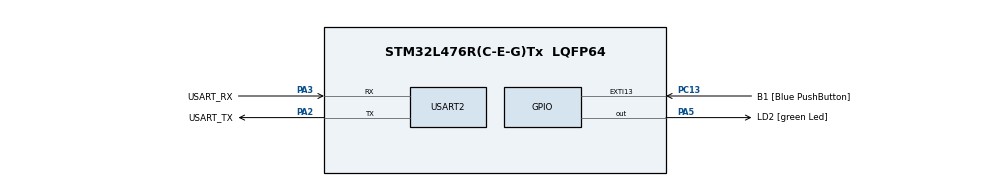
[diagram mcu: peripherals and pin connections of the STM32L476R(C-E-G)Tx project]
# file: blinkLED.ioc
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Mcu.Family=STM32L4
Mcu.Name=STM32L476R(C-E-G)Tx
Mcu.Package=LQFP64
NVIC.PriorityGroup=NVIC_PRIORITYGROUP_4
NVIC.TIM6_DAC_IRQn=true\:0\:0\:false\:false\:true\:true
PA13\ (JTMS-SWDIO).GPIO_Label=TMS
PA13\ (JTMS-SWDIO).Mode=Serial_Wire
PA13\ (JTMS-SWDIO).Signal=SYS_JTMS-SWDIO
PA14\ (JTCK-SWCLK).GPIO_Label=TCK
PA14\ (JTCK-SWCLK).Mode=Serial_Wire
PA14\ (JTCK-SWCLK).Signal=SYS_JTCK-SWCLK
PA2.GPIO_Label=USART_TX
PA2.GPIO_Mode=GPIO_MODE_AF_PP
PA2.GPIO_PuPd=GPIO_NOPULL
PA2.GPIO_Speed=GPIO_SPEED_FREQ_VERY_HIGH
PA2.Mode=Asynchronous
PA2.Signal=USART2_TX
PA3.GPIO_Label=USART_RX
PA3.GPIO_Mode=GPIO_MODE_AF_PP
PA3.GPIO_PuPd=GPIO_NOPULL
PA3.GPIO_Speed=GPIO_SPEED_FREQ_VERY_HIGH
PA3.Mode=Asynchronous
PA3.Signal=USART2_RX
PA5.GPIO_Label=LD2 [green Led]
PA5.GPIO_ModeDefaultOutputPP=GPIO_MODE_OUTPUT_PP
PA5.GPIO_PuPd=GPIO_NOPULL
PA5.GPIO_Speed=GPIO_SPEED_FREQ_LOW
PA5.Signal=GPIO_Output
PB3\ (JTDO-TRACESWO).GPIO_Label=SWO
PB3\ (JTDO-TRACESWO).Signal=SYS_JTDO-SWO
PC13.GPIO_Label=B1 [Blue PushButton]
PC13.GPIO_ModeDefaultEXTI=GPIO_MODE_IT_FALLING
PC13.GPIO_PuPd=GPIO_NOPULL
PC13.Signal=GPXTI13
PC14-OSC32_IN\ (PC14).Mode=LSE-External-Oscillator
PC14-OSC32_IN\ (PC14).Signal=RCC_OSC32_IN
PC15-OSC32_OUT\ (PC15).Mode=LSE-External-Oscillator
PC15-OSC32_OUT\ (PC15).Signal=RCC_OSC32_OUT
PH0-OSC_IN\ (PH0).Signal=RCC_OSC_IN
PH1-OSC_OUT\ (PH1).Signal=RCC_OSC_OUT
ProjectManager.HeapSize=0x200
ProjectManager.StackSize=0x400
ProjectManager.TargetToolchain=SW4STM32
RCC.ADCFreq_Value=64000000
RCC.AHBFreq_Value=16000000
RCC.APB1Freq_Value=16000000
RCC.APB1TimFreq_Value=16000000
RCC.APB2Freq_Value=16000000
RCC.APB2TimFreq_Value=16000000
RCC.CortexFreq_Value=16000000
RCC.HCLKFreq_Value=16000000
RCC.HSE_VALUE=8000000
RCC.HSI_VALUE=16000000
RCC.MSI_VALUE=4000000
RCC.PLLN=10
RCC.PLLSourceVirtual=RCC_PLLSOURCE_HSI
RCC.PREFETCH_ENABLE=1
RCC.SYSCLKFreq_VALUE=16000000
RCC.SYSCLKSource=RCC_SYSCLKSOURCE_HSI
RCC.USBFreq_Value=64000000
RCC.VCOOutputFreq_Value=160000000
TIM6.Period=1000
TIM6.Prescaler=16000
USART2.VirtualMode-Asynchronous=VM_ASYNC
VP_TIM6_VS_ClockSourceINT.Mode=Enable_Timer
board=NUCLEO-L476RG

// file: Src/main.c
/**
  ******************************************************************************
  * @file           : main.c
  * @brief          : Main program body
  ******************************************************************************
  ** This notice applies to any and all portions of this file
  * that are not between comment pairs USER CODE BEGIN and
  * USER CODE END. Other portions of this file, whether
  * inserted by the user or by software development tools
  * are owned by their respective copyright owners.
  *
  * COPYRIGHT(c) 2018 STMicroelectronics
  *
  * Redistribution and use in source and binary forms, with or without modification,
  * are permitted provided that the following conditions are met:
  *   1. Redistributions of source code must retain the above copyright notice,
  *      this list of conditions and the following disclaimer.
  *   2. Redistributions in binary form must reproduce the above copyright notice,
  *      this list of conditions and the following disclaimer in the documentation
  *      and/or other materials provided with the distribution.
  *   3. Neither the name of STMicroelectronics nor the names of its contributors
  *      may be used to endorse or promote products derived from this software
  *      without specific prior written permission.
  *
  * THIS SOFTWARE IS PROVIDED BY THE COPYRIGHT HOLDERS AND CONTRIBUTORS "AS IS"
  * AND ANY EXPRESS OR IMPLIED WARRANTIES, INCLUDING, BUT NOT LIMITED TO, THE
  * IMPLIED WARRANTIES OF MERCHANTABILITY AND FITNESS FOR A PARTICULAR PURPOSE ARE
  * DISCLAIMED. IN NO EVENT SHALL THE COPYRIGHT HOLDER OR CONTRIBUTORS BE LIABLE
  * FOR ANY DIRECT, INDIRECT, INCIDENTAL, SPECIAL, EXEMPLARY, OR CONSEQUENTIAL
  * DAMAGES (INCLUDING, BUT NOT LIMITED TO, PROCUREMENT OF SUBSTITUTE GOODS OR
  * SERVICES; LOSS OF USE, DATA, OR PROFITS; OR BUSINESS INTERRUPTION) HOWEVER
  * CAUSED AND ON ANY THEORY OF LIABILITY, WHETHER IN CONTRACT, STRICT LIABILITY,
  * OR TORT (INCLUDING NEGLIGENCE OR OTHERWISE) ARISING IN ANY WAY OUT OF THE USE
  * OF THIS SOFTWARE, EVEN IF ADVISED OF THE POSSIBILITY OF SUCH DAMAGE.
  *
  ******************************************************************************
  */
#include "main.h"
#include "stm32l4xx_hal.h"

TIM_HandleTypeDef htim6;

UART_HandleTypeDef huart2;

/* USER CODE BEGIN PV */
/* Private variables ---------------------------------------------------------*/

/* USER CODE END PV */

void SystemClock_Config(void);
static void MX_GPIO_Init(void);
static void MX_USART2_UART_Init(void);
static void MX_TIM6_Init(void);

/* USER CODE BEGIN PFP */
/* Private function prototypes -----------------------------------------------*/

/* USER CODE END PFP */

/* USER CODE BEGIN 0 */
void HAL_TIM_PeriodElapsedCallback(TIM_HandleTypeDef *htim)		//function that takes a structure as a parameter
{																//the ISR is handled by HAL
	if(htim->Instance == TIM6)									//if the instance is equal to timer 6 value
		HAL_GPIO_TogglePin(GPIOA, GPIO_PIN_5);					//this function handles the LED blinking, the GPIOA is the port and the GPIO_PIN_5 is the pin number on the port
}
/* USER CODE END 0 */

int main(void)
{

  /* MCU Configuration----------------------------------------------------------*/

  /* Reset of all peripherals, Initializes the Flash interface and the Systick. */
  HAL_Init();

  /* Configure the system clock */
  SystemClock_Config();

  /* Initialize all configured peripherals */
  MX_GPIO_Init();
  MX_USART2_UART_Init();
  MX_TIM6_Init();
  /* USER CODE BEGIN 2 */
  //HAL_TIM_Base_Start_IT(&htim6);					//this function will start the timer6 peripheral
  HAL_TIM_Base_Start_IT( &htim6);					//this function will start the timer6 peripheral
  /* USER CODE END 2 */

  /* Infinite loop */
  while (1)
  {

  }

}

void SystemClock_Config(void)
{

  RCC_OscInitTypeDef RCC_OscInitStruct;
  RCC_ClkInitTypeDef RCC_ClkInitStruct;
  RCC_PeriphCLKInitTypeDef PeriphClkInit;

    /**Initializes the CPU, AHB and APB busses clocks
    */
  RCC_OscInitStruct.OscillatorType = RCC_OSCILLATORTYPE_HSI;
  RCC_OscInitStruct.HSIState = RCC_HSI_ON;
  RCC_OscInitStruct.HSICalibrationValue = 16;
  RCC_OscInitStruct.PLL.PLLState = RCC_PLL_ON;
  RCC_OscInitStruct.PLL.PLLSource = RCC_PLLSOURCE_HSI;
  RCC_OscInitStruct.PLL.PLLM = 1;
  RCC_OscInitStruct.PLL.PLLN = 10;
  RCC_OscInitStruct.PLL.PLLP = RCC_PLLP_DIV7;
  RCC_OscInitStruct.PLL.PLLQ = RCC_PLLQ_DIV2;
  RCC_OscInitStruct.PLL.PLLR = RCC_PLLR_DIV2;
  if (HAL_RCC_OscConfig(&RCC_OscInitStruct) != HAL_OK)
  {
    _Error_Handler(__FILE__, __LINE__);
  }

    /**Initializes the CPU, AHB and APB busses clocks
    */
  RCC_ClkInitStruct.ClockType = RCC_CLOCKTYPE_HCLK|RCC_CLOCKTYPE_SYSCLK
                              |RCC_CLOCKTYPE_PCLK1|RCC_CLOCKTYPE_PCLK2;
  RCC_ClkInitStruct.SYSCLKSource = RCC_SYSCLKSOURCE_PLLCLK;
  RCC_ClkInitStruct.AHBCLKDivider = RCC_SYSCLK_DIV1;
  RCC_ClkInitStruct.APB1CLKDivider = RCC_HCLK_DIV1;
  RCC_ClkInitStruct.APB2CLKDivider = RCC_HCLK_DIV1;

  if (HAL_RCC_ClockConfig(&RCC_ClkInitStruct, FLASH_LATENCY_4) != HAL_OK)
  {
    _Error_Handler(__FILE__, __LINE__);
  }

  PeriphClkInit.PeriphClockSelection = RCC_PERIPHCLK_USART2;
  PeriphClkInit.Usart2ClockSelection = RCC_USART2CLKSOURCE_PCLK1;
  if (HAL_RCCEx_PeriphCLKConfig(&PeriphClkInit) != HAL_OK)
  {
    _Error_Handler(__FILE__, __LINE__);
  }

    /**Configure the main internal regulator output voltage
    */
  if (HAL_PWREx_ControlVoltageScaling(PWR_REGULATOR_VOLTAGE_SCALE1) != HAL_OK)
  {
    _Error_Handler(__FILE__, __LINE__);
  }

    /**Configure the Systick interrupt time
    */
  HAL_SYSTICK_Config(HAL_RCC_GetHCLKFreq()/1000);

    /**Configure the Systick
    */
  HAL_SYSTICK_CLKSourceConfig(SYSTICK_CLKSOURCE_HCLK);

  /* SysTick_IRQn interrupt configuration */
  HAL_NVIC_SetPriority(SysTick_IRQn, 0, 0);
}

/* TIM6 init function */
static void MX_TIM6_Init(void)
{

  TIM_MasterConfigTypeDef sMasterConfig;

  htim6.Instance = TIM6;
  htim6.Init.Prescaler = 39999;
  htim6.Init.CounterMode = TIM_COUNTERMODE_UP;
  htim6.Init.Period = 499;
  htim6.Init.AutoReloadPreload = TIM_AUTORELOAD_PRELOAD_DISABLE;
  if (HAL_TIM_Base_Init(&htim6) != HAL_OK)
  {
    _Error_Handler(__FILE__, __LINE__);
  }

  sMasterConfig.MasterOutputTrigger = TIM_TRGO_RESET;
  sMasterConfig.MasterSlaveMode = TIM_MASTERSLAVEMODE_DISABLE;
  if (HAL_TIMEx_MasterConfigSynchronization(&htim6, &sMasterConfig) != HAL_OK)
  {
    _Error_Handler(__FILE__, __LINE__);
  }

}

/* USART2 init function */
static void MX_USART2_UART_Init(void)
{

  huart2.Instance = USART2;
  huart2.Init.BaudRate = 115200;
  huart2.Init.WordLength = UART_WORDLENGTH_7B;
  huart2.Init.StopBits = UART_STOPBITS_1;
  huart2.Init.Parity = UART_PARITY_NONE;
  huart2.Init.Mode = UART_MODE_TX_RX;
  huart2.Init.HwFlowCtl = UART_HWCONTROL_NONE;
  huart2.Init.OverSampling = UART_OVERSAMPLING_16;
  huart2.Init.OneBitSampling = UART_ONE_BIT_SAMPLE_DISABLE;
  huart2.AdvancedInit.AdvFeatureInit = UART_ADVFEATURE_NO_INIT;
  if (HAL_UART_Init(&huart2) != HAL_OK)
  {
    _Error_Handler(__FILE__, __LINE__);
  }

}

/** Configure pins as
        * Analog
        * Input
        * Output
        * EVENT_OUT
        * EXTI
*/
static void MX_GPIO_Init(void)
{

  GPIO_InitTypeDef GPIO_InitStruct;

  /* GPIO Ports Clock Enable */
  __HAL_RCC_GPIOC_CLK_ENABLE();
  __HAL_RCC_GPIOH_CLK_ENABLE();
  __HAL_RCC_GPIOA_CLK_ENABLE();
  __HAL_RCC_GPIOB_CLK_ENABLE();

  /*Configure GPIO pin Output Level */
  HAL_GPIO_WritePin(LD2_GPIO_Port, LD2_Pin, GPIO_PIN_RESET);

  /*Configure GPIO pin : B1_Pin */
  GPIO_InitStruct.Pin = B1_Pin;
  GPIO_InitStruct.Mode = GPIO_MODE_IT_FALLING;
  GPIO_InitStruct.Pull = GPIO_NOPULL;
  HAL_GPIO_Init(B1_GPIO_Port, &GPIO_InitStruct);

  /*Configure GPIO pin : LD2_Pin */
  GPIO_InitStruct.Pin = LD2_Pin;
  GPIO_InitStruct.Mode = GPIO_MODE_OUTPUT_PP;
  GPIO_InitStruct.Pull = GPIO_NOPULL;
  GPIO_InitStruct.Speed = GPIO_SPEED_FREQ_LOW;
  HAL_GPIO_Init(LD2_GPIO_Port, &GPIO_InitStruct);

}

void _Error_Handler(char *file, int line)
{
  while(1)
  {
  }
}

/************************ (C) COPYRIGHT STMicroelectronics *****END OF FILE****/
